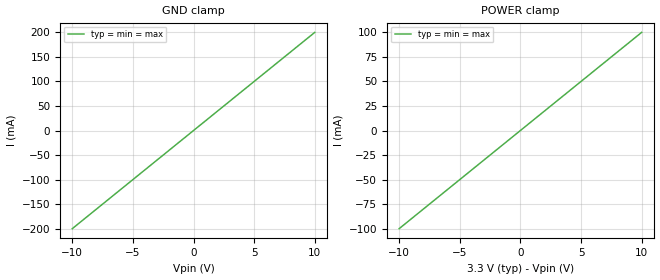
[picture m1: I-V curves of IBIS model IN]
[IBIS Ver] 4.2
[Component] test
[Pin] signal_name model_name
1 D1 IN
2 D2 IN
3 VDD POWER
4 VSS GND
| Models and submodels in the file (1): IN (Input)
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[Model] IN
Model_type Input
C_comp 1p 1p 1p
[Voltage Range] 3.3 3.3 3.3
[Power Clamp]
-10V      -100mA     -100mA     -100mA
10V       100mA      100mA      100mA
[Gnd Clamp]
-10V      -200mA     -200mA     -200mA
10V       200mA      200mA      200mA
